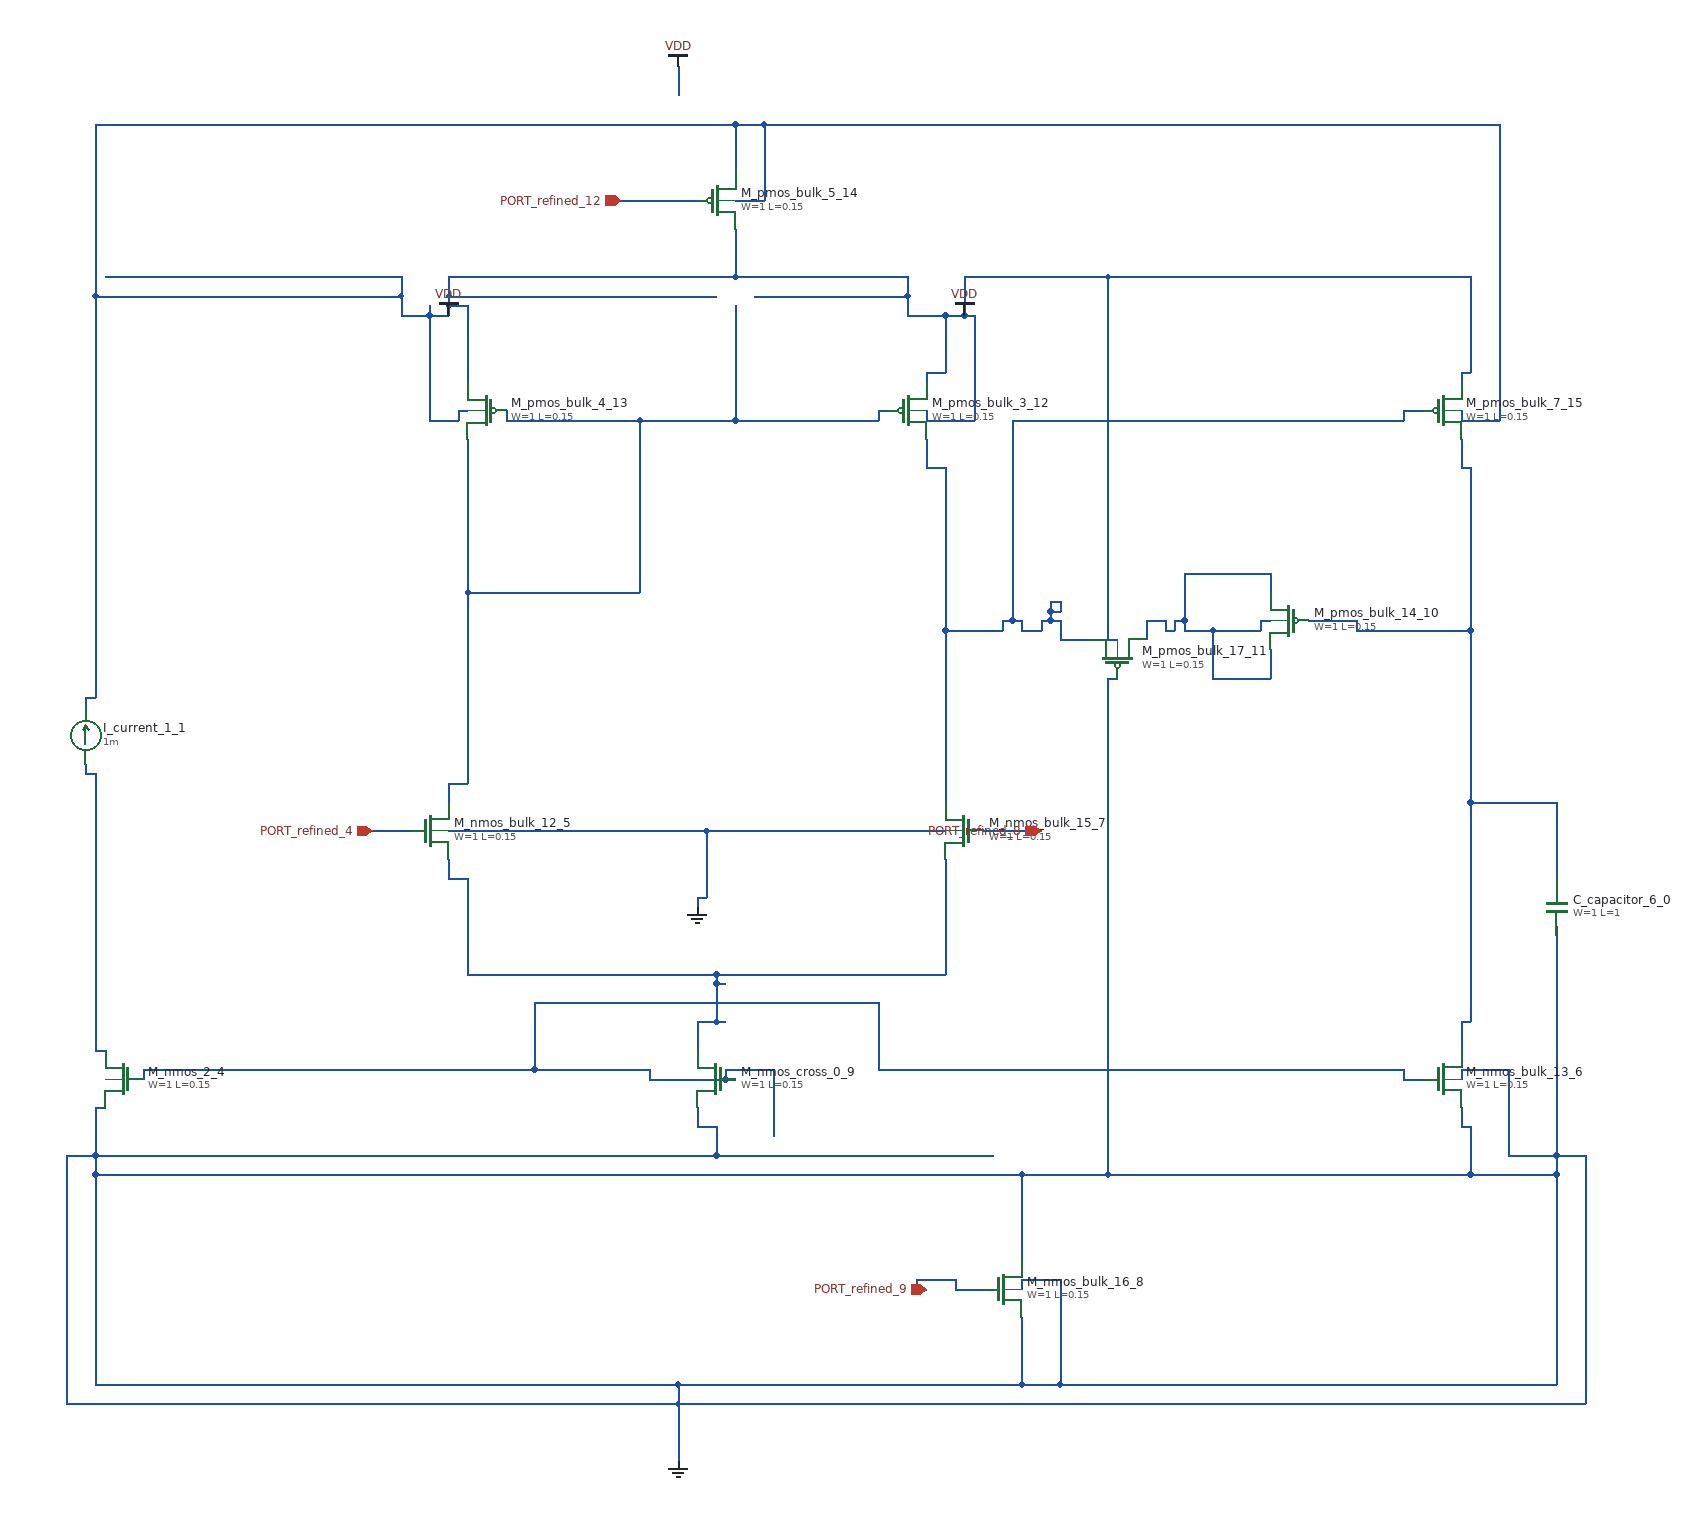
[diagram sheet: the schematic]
v {xschem version=3.4.8 file_version=1.2}
G {}
K {}
V {}
S {}
E {}
C {sky130_fd_pr/cap_mim_m3_1.sym} 1620 900 2 0 {name="C_capacitor_6_0" model=cap_mim_m3_1 W=1 L=1 MF=1 spiceprefix=X}
C {devices/isource.sym} 80 720 2 0 {name="I_current_1_1" value=1m}
C {devices/gnd.sym} 720 900 0 0 {name="l_gnd_8_2" lab="GND"}
C {devices/gnd.sym} 700 1480 0 0 {name="l_gnd_9_3" lab="GND"}
C {sky130_fd_pr/nfet3_01v8.sym} 120 1080 0 1 {name="M_nmos_2_4"
W=1
L=0.15
body=GND
nf=1
mult=1
ad="expr('int((@nf + 1)/2) * @W / @nf * 0.29')"
pd="expr('2*int((@nf + 1)/2) * (@W / @nf + 0.29)')"
as="expr('int((@nf + 2)/2) * @W / @nf * 0.29')"
ps="expr('2*int((@nf + 2)/2) * (@W / @nf + 0.29)')"
nrd="expr('0.29 / @W ')" nrs="expr('0.29 / @W ')"
sa=0 sb=0 sd=0
model=nfet_01v8
spiceprefix=X
}
C {sky130_fd_pr/nfet_01v8.sym} 440 820 0 0 {name="M_nmos_bulk_12_5"
W=1
L=0.15
nf=1 
mult=1
ad="expr('int((@nf + 1)/2) * @W / @nf * 0.29')"
pd="expr('2*int((@nf + 1)/2) * (@W / @nf + 0.29)')"
as="expr('int((@nf + 2)/2) * @W / @nf * 0.29')"
ps="expr('2*int((@nf + 2)/2) * (@W / @nf + 0.29)')"
nrd="expr('0.29 / @W ')" nrs="expr('0.29 / @W ')"
sa=0 sb=0 sd=0
model=nfet_01v8
spiceprefix=X
}
C {sky130_fd_pr/nfet_01v8.sym} 1500 1080 0 0 {name="M_nmos_bulk_13_6"
W=1
L=0.15
nf=1 
mult=1
ad="expr('int((@nf + 1)/2) * @W / @nf * 0.29')"
pd="expr('2*int((@nf + 1)/2) * (@W / @nf + 0.29)')"
as="expr('int((@nf + 2)/2) * @W / @nf * 0.29')"
ps="expr('2*int((@nf + 2)/2) * (@W / @nf + 0.29)')"
nrd="expr('0.29 / @W ')" nrs="expr('0.29 / @W ')"
sa=0 sb=0 sd=0
model=nfet_01v8
spiceprefix=X
}
C {sky130_fd_pr/nfet_01v8.sym} 1000 820 0 1 {name="M_nmos_bulk_15_7"
W=1
L=0.15
nf=1 
mult=1
ad="expr('int((@nf + 1)/2) * @W / @nf * 0.29')"
pd="expr('2*int((@nf + 1)/2) * (@W / @nf + 0.29)')"
as="expr('int((@nf + 2)/2) * @W / @nf * 0.29')"
ps="expr('2*int((@nf + 2)/2) * (@W / @nf + 0.29)')"
nrd="expr('0.29 / @W ')" nrs="expr('0.29 / @W ')"
sa=0 sb=0 sd=0
model=nfet_01v8
spiceprefix=X
}
C {sky130_fd_pr/nfet_01v8.sym} 1040 1300 0 0 {name="M_nmos_bulk_16_8"
W=1
L=0.15
nf=1 
mult=1
ad="expr('int((@nf + 1)/2) * @W / @nf * 0.29')"
pd="expr('2*int((@nf + 1)/2) * (@W / @nf + 0.29)')"
as="expr('int((@nf + 2)/2) * @W / @nf * 0.29')"
ps="expr('2*int((@nf + 2)/2) * (@W / @nf + 0.29)')"
nrd="expr('0.29 / @W ')" nrs="expr('0.29 / @W ')"
sa=0 sb=0 sd=0
model=nfet_01v8
spiceprefix=X
}
C {sky130_fd_pr/nfet3_01v8.sym} 740 1080 0 1 {name="M_nmos_cross_0_9"
W=1
L=0.15
body=GND
nf=1
mult=1
ad="expr('int((@nf + 1)/2) * @W / @nf * 0.29')"
pd="expr('2*int((@nf + 1)/2) * (@W / @nf + 0.29)')"
as="expr('int((@nf + 2)/2) * @W / @nf * 0.29')"
ps="expr('2*int((@nf + 2)/2) * (@W / @nf + 0.29)')"
nrd="expr('0.29 / @W ')" nrs="expr('0.29 / @W ')"
sa=0 sb=0 sd=0
model=nfet_01v8
spiceprefix=X
}
C {sky130_fd_pr/pfet_01v8.sym} 1340 600 0 1 {name="M_pmos_bulk_14_10"
W=1
L=0.15
nf=1
mult=1
ad="expr('int((@nf + 1)/2) * @W / @nf * 0.29')"
pd="expr('2*int((@nf + 1)/2) * (@W / @nf + 0.29)')"
as="expr('int((@nf + 2)/2) * @W / @nf * 0.29')"
ps="expr('2*int((@nf + 2)/2) * (@W / @nf + 0.29)')"
nrd="expr('0.29 / @W ')" nrs="expr('0.29 / @W ')"
sa=0 sb=0 sd=0
model=pfet_01v8
spiceprefix=X
}
C {sky130_fd_pr/pfet_01v8.sym} 1160 640 1 1 {name="M_pmos_bulk_17_11"
W=1
L=0.15
nf=1
mult=1
ad="expr('int((@nf + 1)/2) * @W / @nf * 0.29')"
pd="expr('2*int((@nf + 1)/2) * (@W / @nf + 0.29)')"
as="expr('int((@nf + 2)/2) * @W / @nf * 0.29')"
ps="expr('2*int((@nf + 2)/2) * (@W / @nf + 0.29)')"
nrd="expr('0.29 / @W ')" nrs="expr('0.29 / @W ')"
sa=0 sb=0 sd=0
model=pfet_01v8
spiceprefix=X
}
C {sky130_fd_pr/pfet_01v8.sym} 940 380 0 0 {name="M_pmos_bulk_3_12"
W=1
L=0.15
nf=1
mult=1
ad="expr('int((@nf + 1)/2) * @W / @nf * 0.29')"
pd="expr('2*int((@nf + 1)/2) * (@W / @nf + 0.29)')"
as="expr('int((@nf + 2)/2) * @W / @nf * 0.29')"
ps="expr('2*int((@nf + 2)/2) * (@W / @nf + 0.29)')"
nrd="expr('0.29 / @W ')" nrs="expr('0.29 / @W ')"
sa=0 sb=0 sd=0
model=pfet_01v8
spiceprefix=X
}
C {sky130_fd_pr/pfet_01v8.sym} 500 380 0 1 {name="M_pmos_bulk_4_13"
W=1
L=0.15
nf=1
mult=1
ad="expr('int((@nf + 1)/2) * @W / @nf * 0.29')"
pd="expr('2*int((@nf + 1)/2) * (@W / @nf + 0.29)')"
as="expr('int((@nf + 2)/2) * @W / @nf * 0.29')"
ps="expr('2*int((@nf + 2)/2) * (@W / @nf + 0.29)')"
nrd="expr('0.29 / @W ')" nrs="expr('0.29 / @W ')"
sa=0 sb=0 sd=0
model=pfet_01v8
spiceprefix=X
}
C {sky130_fd_pr/pfet_01v8.sym} 740 160 0 0 {name="M_pmos_bulk_5_14"
W=1
L=0.15
nf=1
mult=1
ad="expr('int((@nf + 1)/2) * @W / @nf * 0.29')"
pd="expr('2*int((@nf + 1)/2) * (@W / @nf + 0.29)')"
as="expr('int((@nf + 2)/2) * @W / @nf * 0.29')"
ps="expr('2*int((@nf + 2)/2) * (@W / @nf + 0.29)')"
nrd="expr('0.29 / @W ')" nrs="expr('0.29 / @W ')"
sa=0 sb=0 sd=0
model=pfet_01v8
spiceprefix=X
}
C {sky130_fd_pr/pfet_01v8.sym} 1500 380 0 0 {name="M_pmos_bulk_7_15"
W=1
L=0.15
nf=1
mult=1
ad="expr('int((@nf + 1)/2) * @W / @nf * 0.29')"
pd="expr('2*int((@nf + 1)/2) * (@W / @nf + 0.29)')"
as="expr('int((@nf + 2)/2) * @W / @nf * 0.29')"
ps="expr('2*int((@nf + 2)/2) * (@W / @nf + 0.29)')"
nrd="expr('0.29 / @W ')" nrs="expr('0.29 / @W ')"
sa=0 sb=0 sd=0
model=pfet_01v8
spiceprefix=X
}
C {devices/ipin.sym} 380 820 0 0 {name="p_port_10_16" lab="PORT_refined_4"}
C {devices/ipin.sym} 1080 820 0 0 {name="p_port_11_17" lab="PORT_refined_8"}
C {devices/ipin.sym} 640 160 0 0 {name="p_port_22_18" lab="PORT_refined_12"}
C {devices/ipin.sym} 960 1300 0 0 {name="p_port_23_19" lab="PORT_refined_9"}
C {devices/vdd.sym} 700 20 0 0 {name="l_vdd_18_20" lab="VDD"}
C {devices/vdd.sym} 1000 280 0 0 {name="l_vdd_19_21" lab="VDD"}
C {devices/vdd.sym} 460 280 0 0 {name="l_vdd_21_22" lab="VDD"}
N 1520 1020 1530 1020 {}
N 1530 790 1620 790 {}
N 1410 610 1530 610 {}
N 1360 600 1410 600 {}
N 1520 440 1530 440 {}
N 1410 610 1410 600 {}
N 1520 1050 1520 1020 {}
N 1520 440 1520 410 {}
N 1530 1020 1530 790 {}
N 1530 790 1530 610 {}
N 1530 610 1530 440 {}
N 1620 870 1620 790 {}
N 60 1420 700 1420 {}
N 700 1420 1650 1420 {}
N 90 1400 700 1400 {}
N 700 1400 1060 1400 {}
N 1060 1400 1100 1400 {}
N 1100 1400 1620 1400 {}
N 1060 1290 1100 1290 {}
N 90 1180 1060 1180 {}
N 1060 1180 1150 1180 {}
N 1150 1180 1530 1180 {}
N 1530 1180 1620 1180 {}
N 60 1160 90 1160 {}
N 90 1160 740 1160 {}
N 740 1160 1030 1160 {}
N 1570 1160 1620 1160 {}
N 1620 1160 1650 1160 {}
N 720 1130 740 1130 {}
N 1520 1130 1530 1130 {}
N 90 1110 100 1110 {}
N 1520 1070 1570 1070 {}
N 720 890 730 890 {}
N 460 820 730 820 {}
N 730 820 980 820 {}
N 1150 660 1160 660 {}
N 60 1420 60 1160 {}
N 90 1400 90 1180 {}
N 90 1180 90 1160 {}
N 90 1160 90 1110 {}
N 700 1480 700 1420 {}
N 700 1420 700 1400 {}
N 720 1130 720 1110 {}
N 720 900 720 890 {}
N 730 890 730 820 {}
N 740 1160 740 1130 {}
N 1060 1400 1060 1330 {}
N 1060 1300 1060 1290 {}
N 1060 1270 1060 1180 {}
N 1100 1400 1100 1290 {}
N 1150 1180 1150 660 {}
N 1520 1130 1520 1110 {}
N 1520 1080 1520 1070 {}
N 1530 1180 1530 1130 {}
N 1570 1160 1570 1070 {}
N 1620 1400 1620 1180 {}
N 1620 1180 1620 1160 {}
N 1620 1160 1620 930 {}
N 1620 930 1620 920 {}
N 1650 1420 1650 1160 {}
N 1260 660 1320 660 {}
N 1210 610 1220 610 {}
N 1230 610 1260 610 {}
N 1260 610 1310 610 {}
N 1190 600 1210 600 {}
N 1220 600 1230 600 {}
N 1310 600 1320 600 {}
N 1230 550 1320 550 {}
N 1190 620 1190 600 {}
N 1210 610 1210 600 {}
N 1220 610 1220 600 {}
N 1230 610 1230 600 {}
N 1230 600 1230 550 {}
N 1260 660 1260 610 {}
N 1310 610 1310 600 {}
N 1320 660 1320 630 {}
N 1320 570 1320 550 {}
N 80 680 90 680 {}
N 1150 620 1160 620 {}
N 440 390 470 390 {}
N 960 390 1010 390 {}
N 1520 390 1560 390 {}
N 470 380 480 380 {}
N 960 340 980 340 {}
N 1520 340 1530 340 {}
N 410 280 440 280 {}
N 440 280 460 280 {}
N 940 280 980 280 {}
N 980 280 1000 280 {}
N 1000 280 1010 280 {}
N 460 270 480 270 {}
N 90 260 410 260 {}
N 460 260 740 260 {}
N 780 260 940 260 {}
N 100 240 410 240 {}
N 460 240 760 240 {}
N 760 240 940 240 {}
N 1000 240 1150 240 {}
N 1150 240 1530 240 {}
N 760 160 790 160 {}
N 90 80 760 80 {}
N 760 80 790 80 {}
N 790 80 1560 80 {}
N 80 690 80 680 {}
N 90 680 90 260 {}
N 90 260 90 80 {}
N 410 280 410 260 {}
N 410 260 410 240 {}
N 440 390 440 280 {}
N 440 280 440 270 {}
N 460 280 460 270 {}
N 460 270 460 260 {}
N 460 260 460 240 {}
N 470 390 470 380 {}
N 480 350 480 270 {}
N 700 50 700 20 {}
N 760 240 760 190 {}
N 760 130 760 80 {}
N 790 160 790 80 {}
N 940 280 940 260 {}
N 940 260 940 240 {}
N 960 390 960 380 {}
N 960 350 960 340 {}
N 980 340 980 280 {}
N 1000 280 1000 240 {}
N 1010 390 1010 280 {}
N 1150 620 1150 240 {}
N 1520 390 1520 380 {}
N 1520 350 1520 340 {}
N 1530 340 1530 240 {}
N 1560 390 1560 80 {}
N 640 160 720 160 {}
N 460 770 480 770 {}
N 480 570 660 570 {}
N 520 390 660 390 {}
N 660 390 760 390 {}
N 760 390 910 390 {}
N 910 380 920 380 {}
N 460 790 460 770 {}
N 480 770 480 570 {}
N 480 570 480 410 {}
N 520 390 520 380 {}
N 660 570 660 390 {}
N 760 390 760 270 {}
N 910 390 910 380 {}
N 720 1020 740 1020 {}
N 740 1020 750 1020 {}
N 740 980 750 980 {}
N 480 970 740 970 {}
N 740 970 980 970 {}
N 460 870 480 870 {}
N 460 870 460 850 {}
N 480 970 480 870 {}
N 720 1050 720 1020 {}
N 740 1020 740 980 {}
N 740 980 740 970 {}
N 980 970 980 850 {}
N 380 820 420 820 {}
N 670 1080 750 1080 {}
N 750 1080 760 1080 {}
N 1460 1080 1480 1080 {}
N 140 1070 550 1070 {}
N 550 1070 670 1070 {}
N 750 1070 800 1070 {}
N 910 1070 1460 1070 {}
N 550 1000 910 1000 {}
N 140 1080 140 1070 {}
N 550 1070 550 1000 {}
N 670 1080 670 1070 {}
N 750 1080 750 1070 {}
N 800 1140 800 1070 {}
N 910 1070 910 1000 {}
N 1460 1080 1460 1070 {}
N 1100 620 1130 620 {}
N 980 610 1040 610 {}
N 1060 610 1080 610 {}
N 1040 600 1050 600 {}
N 1050 600 1060 600 {}
N 1080 600 1090 600 {}
N 1090 600 1100 600 {}
N 1090 590 1100 590 {}
N 1090 580 1100 580 {}
N 960 440 980 440 {}
N 1050 390 1460 390 {}
N 1460 380 1480 380 {}
N 960 440 960 410 {}
N 980 790 980 610 {}
N 980 610 980 440 {}
N 1040 610 1040 600 {}
N 1050 600 1050 390 {}
N 1060 610 1060 600 {}
N 1080 610 1080 600 {}
N 1090 600 1090 590 {}
N 1090 590 1090 580 {}
N 1100 620 1100 600 {}
N 1100 590 1100 580 {}
N 1460 390 1460 380 {}
N 90 1050 100 1050 {}
N 80 760 90 760 {}
N 80 760 80 750 {}
N 90 1050 90 760 {}
N 1020 820 1080 820 {}
N 950 1300 960 1300 {}
N 990 1300 1020 1300 {}
N 950 1290 990 1290 {}
N 950 1300 950 1290 {}
N 990 1300 990 1290 {}
